VERSION 5.7 ;

BUSBITCHARS "[]" ;
DIVIDERCHAR "/" ;

UNITS
  TIME NANOSECONDS 1 ;
  CAPACITANCE PICOFARADS 1 ;
  RESISTANCE OHMS 1 ;
  DATABASE MICRONS 1000 ;
END UNITS

MANUFACTURINGGRID 0.005 ;

PROPERTYDEFINITIONS
  LAYER LEF58_TYPE STRING ;
END PROPERTYDEFINITIONS

SITE unithd
  SYMMETRY Y ;
  CLASS CORE ;
  SIZE 0.46 BY 2.72 ;
END unithd

SITE unithddbl
  SYMMETRY Y ;
  CLASS CORE ;
  SIZE 0.46 BY 5.44 ;
END unithddbl

LAYER nwell
  TYPE MASTERSLICE ;
 PROPERTY LEF58_TYPE "TYPE NWELL ;" ;
END nwell

LAYER pwell
  TYPE MASTERSLICE ;
 PROPERTY LEF58_TYPE "TYPE PWELL ;" ;
END pwell

LAYER Gate
  TYPE MASTERSLICE ;
END Gate

LAYER Active
  TYPE MASTERSLICE ;
END Active

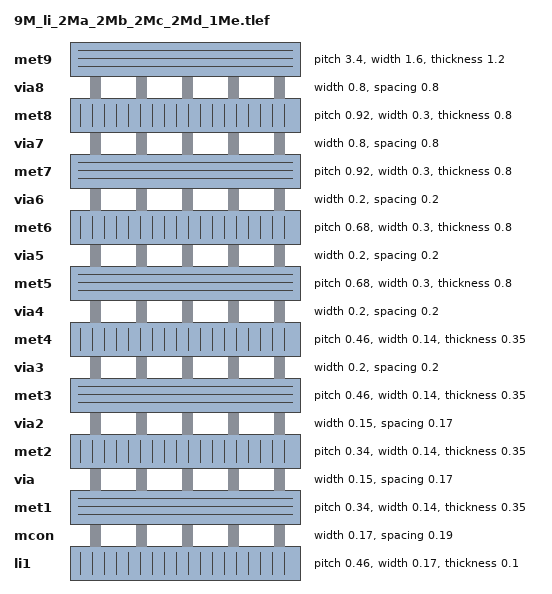
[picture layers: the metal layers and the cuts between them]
LAYER li1
  TYPE ROUTING ;
  DIRECTION VERTICAL ;

  PITCH 0.46 0.34 ;
  OFFSET 0.23 0.17 ;

  WIDTH 0.17 ;
  SPACINGTABLE
     PARALLELRUNLENGTH 0
     WIDTH 0 0.17 ;
  AREA 0.0561 ;
  THICKNESS 0.1 ;
  EDGECAPACITANCE 40.697E-6 ;
  CAPACITANCE CPERSQDIST 36.9866E-6 ;
  RESISTANCE RPERSQ 12.2 ;

  ANTENNAMODEL OXIDE1 ;
  ANTENNADIFFSIDEAREARATIO PWL ( ( 0 75 ) ( 0.0125 75 ) ( 0.0225 85.125 ) ( 22.5 10200 ) ) ;
END li1

LAYER mcon
  TYPE CUT ;

  WIDTH 0.17 ;
  SPACING 0.19 ;
  ENCLOSURE BELOW 0 0 ;
  ENCLOSURE ABOVE 0.03 0.06 ;

  ANTENNADIFFAREARATIO PWL ( ( 0 3 ) ( 0.0125 3 ) ( 0.0225 3.405 ) ( 22.5 408 ) ) ;
  DCCURRENTDENSITY AVERAGE 0.36 ;

END mcon
LAYER met1
  TYPE ROUTING ;
  DIRECTION HORIZONTAL ;

  PITCH 0.34 ;
  OFFSET 0.17 ;

  WIDTH 0.14 ;
  SPACINGTABLE
     PARALLELRUNLENGTH 0
     WIDTH 0 0.14
     WIDTH 3 0.28 ;
  AREA 0.083 ;
  THICKNESS 0.35 ;
  MINENCLOSEDAREA 0.14 ;

  ANTENNAMODEL OXIDE1 ;
  ANTENNADIFFSIDEAREARATIO PWL ( ( 0 400 ) ( 0.0125 400 ) ( 0.0225 2609 ) ( 22.5 11600 ) ) ;

  EDGECAPACITANCE 40.567E-6 ;
  CAPACITANCE CPERSQDIST 25.7784E-6 ;
  DCCURRENTDENSITY AVERAGE 2.8 ;
  ACCURRENTDENSITY RMS 6.1 ;
  MAXIMUMDENSITY 70 ;
  DENSITYCHECKWINDOW 700 700 ;
  DENSITYCHECKSTEP 70 ;

  RESISTANCE RPERSQ 0.125 ;
END met1
LAYER via
  TYPE CUT ;
  WIDTH 0.15 ; 
  SPACING 0.17 ;
  ENCLOSURE BELOW 0.055 0.085 ;
  ENCLOSURE ABOVE 0.055 0.085 ;
  ANTENNADIFFAREARATIO PWL ( ( 0 6 ) ( 0.0125 6 ) ( 0.0225 6.81 ) ( 22.5 816 ) ) ;
  DCCURRENTDENSITY AVERAGE 0.29 ;
END via
LAYER met2
  TYPE ROUTING ;
  DIRECTION VERTICAL ;

  PITCH 0.34 ;
  OFFSET 0.17 ;

  WIDTH 0.14 ;
  SPACINGTABLE
     PARALLELRUNLENGTH 0
     WIDTH 0 0.14
     WIDTH 3 0.28 ;
  AREA 0.083 ;
  THICKNESS 0.35 ;
  MINENCLOSEDAREA 0.14 ;

  ANTENNAMODEL OXIDE1 ;
  ANTENNADIFFSIDEAREARATIO PWL ( ( 0 400 ) ( 0.0125 400 ) ( 0.0225 2609 ) ( 22.5 11600 ) ) ;

  EDGECAPACITANCE 40.567E-6 ;
  CAPACITANCE CPERSQDIST 25.7784E-6 ;
  DCCURRENTDENSITY AVERAGE 2.8 ;
  ACCURRENTDENSITY RMS 6.1 ;
  MAXIMUMDENSITY 70 ;
  DENSITYCHECKWINDOW 700 700 ;
  DENSITYCHECKSTEP 70 ;

  RESISTANCE RPERSQ 0.125 ;
END met2
LAYER via2
  TYPE CUT ;
  WIDTH 0.15 ; 
  SPACING 0.17 ;
  ENCLOSURE BELOW 0.055 0.085 ;
  ENCLOSURE ABOVE 0.055 0.085 ;
  ANTENNADIFFAREARATIO PWL ( ( 0 6 ) ( 0.0125 6 ) ( 0.0225 6.81 ) ( 22.5 816 ) ) ;
  DCCURRENTDENSITY AVERAGE 0.29 ;
END via2
LAYER met3
  TYPE ROUTING ;
  DIRECTION HORIZONTAL ;

  PITCH 0.46 ;
  OFFSET 0.23 ;

  WIDTH 0.14 ; 
  SPACINGTABLE
     PARALLELRUNLENGTH 0
     WIDTH 0 0.14
     WIDTH 3 0.28 ;
  AREA 0.0676 ;
  THICKNESS 0.35 ;
  MINENCLOSEDAREA 0.14 ;

  EDGECAPACITANCE 37.759E-6 ;
  CAPACITANCE CPERSQDIST 16.9423E-6 ;
  RESISTANCE RPERSQ 0.125 ;
  DCCURRENTDENSITY AVERAGE 2.8 ;
  ACCURRENTDENSITY RMS 6.1 ;

  ANTENNAMODEL OXIDE1 ;
  ANTENNADIFFSIDEAREARATIO PWL ( ( 0 400 ) ( 0.0125 400 ) ( 0.0225 2609 ) ( 22.5 11600 ) ) ;

  MAXIMUMDENSITY 70 ;
  DENSITYCHECKWINDOW 700 700 ;
  DENSITYCHECKSTEP 70 ;
END met3
LAYER via3
  TYPE CUT ;
  WIDTH 0.2 ;
  SPACING 0.2 ;
  ENCLOSURE BELOW 0.04 0.085 ;
  ENCLOSURE ABOVE 0.065 0.065 ;
  ANTENNADIFFAREARATIO PWL ( ( 0 6 ) ( 0.0125 6 ) ( 0.0225 6.81 ) ( 22.5 816 ) ) ;
  DCCURRENTDENSITY AVERAGE 0.48 ;
END via3
LAYER met4
  TYPE ROUTING ;
  DIRECTION VERTICAL ;

  PITCH 0.46 ;
  OFFSET 0.23 ;

  WIDTH 0.14 ; 
  SPACINGTABLE
     PARALLELRUNLENGTH 0
     WIDTH 0 0.14
     WIDTH 3 0.28 ;
  AREA 0.0676 ;
  THICKNESS 0.35 ;
  MINENCLOSEDAREA 0.14 ;

  EDGECAPACITANCE 37.759E-6 ;
  CAPACITANCE CPERSQDIST 16.9423E-6 ;
  RESISTANCE RPERSQ 0.125 ;
  DCCURRENTDENSITY AVERAGE 2.8 ;
  ACCURRENTDENSITY RMS 6.1 ;

  ANTENNAMODEL OXIDE1 ;
  ANTENNADIFFSIDEAREARATIO PWL ( ( 0 400 ) ( 0.0125 400 ) ( 0.0225 2609 ) ( 22.5 11600 ) ) ;

  MAXIMUMDENSITY 70 ;
  DENSITYCHECKWINDOW 700 700 ;
  DENSITYCHECKSTEP 70 ;
END met4
LAYER via4
  TYPE CUT ;
  WIDTH 0.2 ;
  SPACING 0.2 ;
  ENCLOSURE BELOW 0.04 0.085 ;
  ENCLOSURE ABOVE 0.065 0.065 ;
  ANTENNADIFFAREARATIO PWL ( ( 0 6 ) ( 0.0125 6 ) ( 0.0225 6.81 ) ( 22.5 816 ) ) ;
  DCCURRENTDENSITY AVERAGE 0.48 ;
END via4
LAYER met5
  TYPE ROUTING ;
  DIRECTION HORIZONTAL ;

  PITCH 0.68 ;
  OFFSET 0.34 ;

  WIDTH 0.3 ;
  SPACINGTABLE
     PARALLELRUNLENGTH 0
     WIDTH 0 0.3
     WIDTH 3 0.4 ;
  AREA 0.24 ;              # Met3 6
  THICKNESS 0.8 ;

  EDGECAPACITANCE 40.989E-6 ;
  CAPACITANCE CPERSQDIST 12.3729E-6 ;
  RESISTANCE RPERSQ 0.047 ;
  DCCURRENTDENSITY AVERAGE 6.8 ;
  ACCURRENTDENSITY RMS 14.9 ;

  ANTENNAMODEL OXIDE1 ;
  ANTENNADIFFSIDEAREARATIO PWL ( ( 0 400 ) ( 0.0125 400 ) ( 0.0225 2609 ) ( 22.5 11600 ) ) ;

  MAXIMUMDENSITY 70 ;
  DENSITYCHECKWINDOW 700 700 ;
  DENSITYCHECKSTEP 70 ;
END met5
LAYER via5
  TYPE CUT ;
  WIDTH 0.2 ;
  SPACING 0.2 ;
  ENCLOSURE BELOW 0.06 0.09 ;
  ENCLOSURE ABOVE 0.065 0.065 ;
  ANTENNADIFFAREARATIO PWL ( ( 0 6 ) ( 0.0125 6 ) ( 0.0225 6.81 ) ( 22.5 816 ) ) ;
  DCCURRENTDENSITY AVERAGE 0.48 ;
END via5
LAYER met6
  TYPE ROUTING ;
  DIRECTION VERTICAL ;

  PITCH 0.68 ;
  OFFSET 0.34 ;

  WIDTH 0.3 ;
  SPACINGTABLE
     PARALLELRUNLENGTH 0
     WIDTH 0 0.3
     WIDTH 3 0.4 ;
  AREA 0.24 ;              # Met3 6
  THICKNESS 0.8 ;

  EDGECAPACITANCE 40.989E-6 ;
  CAPACITANCE CPERSQDIST 12.3729E-6 ;
  RESISTANCE RPERSQ 0.047 ;
  DCCURRENTDENSITY AVERAGE 6.8 ;
  ACCURRENTDENSITY RMS 14.9 ;

  ANTENNAMODEL OXIDE1 ;
  ANTENNADIFFSIDEAREARATIO PWL ( ( 0 400 ) ( 0.0125 400 ) ( 0.0225 2609 ) ( 22.5 11600 ) ) ;

  MAXIMUMDENSITY 70 ;
  DENSITYCHECKWINDOW 700 700 ;
  DENSITYCHECKSTEP 70 ;
END met6
LAYER via6
  TYPE CUT ;
  WIDTH 0.2 ;
  SPACING 0.2 ;
  ENCLOSURE BELOW 0.06 0.09 ;
  ENCLOSURE ABOVE 0.065 0.065 ;
  ANTENNADIFFAREARATIO PWL ( ( 0 6 ) ( 0.0125 6 ) ( 0.0225 6.81 ) ( 22.5 816 ) ) ;
  DCCURRENTDENSITY AVERAGE 0.48 ;
END via6
LAYER met7
  TYPE ROUTING ;
  DIRECTION HORIZONTAL ;


  PITCH 0.92 ;
  OFFSET 0.46 ;

  WIDTH 0.3 ;
  SPACINGTABLE
     PARALLELRUNLENGTH 0
     WIDTH 0 0.3
     WIDTH 3 0.4 ;
  AREA 0.24 ;

  THICKNESS 0.8 ;

  EDGECAPACITANCE 36.676E-6 ;
  CAPACITANCE CPERSQDIST 8.41537E-6 ;
  RESISTANCE RPERSQ 0.047 ;
  DCCURRENTDENSITY AVERAGE 6.8 ;
  ACCURRENTDENSITY RMS 14.9 ;

  ANTENNAMODEL OXIDE1 ;
  ANTENNADIFFSIDEAREARATIO PWL ( ( 0 400 ) ( 0.0125 400 ) ( 0.0225 2609 ) ( 22.5 11600 ) ) ;

  MAXIMUMDENSITY 70 ;
  DENSITYCHECKWINDOW 700 700 ;
  DENSITYCHECKSTEP 70 ;
END met7
LAYER via7
  TYPE CUT ;
  WIDTH 0.8 ;
  SPACING 0.8 ;
  ENCLOSURE BELOW 0.19 0.19 ;
  ENCLOSURE ABOVE 0.31 0.31 ;
  ANTENNADIFFAREARATIO PWL ( ( 0 6 ) ( 0.0125 6 ) ( 0.0225 6.81 ) ( 22.5 816 ) ) ;
  DCCURRENTDENSITY AVERAGE 2.49 ;
END via7
LAYER met8
  TYPE ROUTING ;
  DIRECTION VERTICAL ;


  PITCH 0.92 ;
  OFFSET 0.46 ;

  WIDTH 0.3 ;
  SPACINGTABLE
     PARALLELRUNLENGTH 0
     WIDTH 0 0.3
     WIDTH 3 0.4 ;
  AREA 0.24 ;

  THICKNESS 0.8 ;

  EDGECAPACITANCE 36.676E-6 ;
  CAPACITANCE CPERSQDIST 8.41537E-6 ;
  RESISTANCE RPERSQ 0.047 ;
  DCCURRENTDENSITY AVERAGE 6.8 ;
  ACCURRENTDENSITY RMS 14.9 ;

  ANTENNAMODEL OXIDE1 ;
  ANTENNADIFFSIDEAREARATIO PWL ( ( 0 400 ) ( 0.0125 400 ) ( 0.0225 2609 ) ( 22.5 11600 ) ) ;

  MAXIMUMDENSITY 70 ;
  DENSITYCHECKWINDOW 700 700 ;
  DENSITYCHECKSTEP 70 ;
END met8
LAYER via8
  TYPE CUT ;
  WIDTH 0.8 ;
  SPACING 0.8 ;
  ENCLOSURE BELOW 0.19 0.19 ;
  ENCLOSURE ABOVE 0.31 0.31 ;
  ANTENNADIFFAREARATIO PWL ( ( 0 6 ) ( 0.0125 6 ) ( 0.0225 6.81 ) ( 22.5 816 ) ) ;
  DCCURRENTDENSITY AVERAGE 2.49 ;
END via8
LAYER met9
  TYPE ROUTING ;
  DIRECTION HORIZONTAL ;


  PITCH 3.4 ;
  OFFSET 1.7 ;

  WIDTH 1.6 ;
  SPACINGTABLE
     PARALLELRUNLENGTH 0
     WIDTH 0 1.6 ;
  AREA 4 ;

  THICKNESS 1.2 ;

  EDGECAPACITANCE 38.851E-6 ;
  CAPACITANCE CPERSQDIST 6.32063E-6 ;
  RESISTANCE RPERSQ 0.0285 ;
  DCCURRENTDENSITY AVERAGE 10.17 ;
  ACCURRENTDENSITY RMS 22.34 ;

  ANTENNAMODEL OXIDE1 ;
  ANTENNADIFFSIDEAREARATIO PWL ( ( 0 400 ) ( 0.0125 400 ) ( 0.0225 2609 ) ( 22.5 11600 ) ) ;
END met9
### Routing via cells section   ###
# Plus via rule, metals are along the prefered direction
VIA L1M1_PR DEFAULT
  LAYER mcon ;
  RECT -0.085 -0.085 0.085 0.085 ;
  LAYER li1 ;
  RECT -0.085 -0.085 0.085 0.085 ;
  LAYER met1 ;
  RECT -0.145 -0.115 0.145 0.115 ;
END L1M1_PR

VIARULE L1M1_PR GENERATE
  LAYER li1 ;
  ENCLOSURE 0 0 ;
  LAYER met1 ;
  ENCLOSURE 0.06 0.03 ;
  LAYER mcon ;
  RECT -0.085 -0.085 0.085 0.085 ;
  SPACING 0.36 BY 0.36 ;
END L1M1_PR

# Plus via rule, metals are along the non prefered direction
VIA L1M1_PR_R DEFAULT
  LAYER mcon ;
  RECT -0.085 -0.085 0.085 0.085 ;
  LAYER li1 ;
  RECT -0.085 -0.085 0.085 0.085 ;
  LAYER met1 ;
  RECT -0.115 -0.145 0.115 0.145 ;
END L1M1_PR_R

VIARULE L1M1_PR_R GENERATE
  LAYER li1 ;
  ENCLOSURE 0 0 ;
  LAYER met1 ;
  ENCLOSURE 0.03 0.06 ;
  LAYER mcon ;
  RECT -0.085 -0.085 0.085 0.085 ;
  SPACING 0.36 BY 0.36 ;
END L1M1_PR_R

# Minus via rule, lower layer metal is along prefered direction
VIA L1M1_PR_M DEFAULT
  LAYER mcon ;
  RECT -0.085 -0.085 0.085 0.085 ;
  LAYER li1 ;
  RECT -0.085 -0.085 0.085 0.085 ;
  LAYER met1 ;
  RECT -0.115 -0.145 0.115 0.145 ;
END L1M1_PR_M

VIARULE L1M1_PR_M GENERATE
  LAYER li1 ;
  ENCLOSURE 0 0 ;
  LAYER met1 ;
  ENCLOSURE 0.03 0.06 ;
  LAYER mcon ;
  RECT -0.085 -0.085 0.085 0.085 ;
  SPACING 0.36 BY 0.36 ;
END L1M1_PR_M

# Minus via rule, upper layer metal is along prefered direction
VIA L1M1_PR_MR DEFAULT
  LAYER mcon ;
  RECT -0.085 -0.085 0.085 0.085 ;
  LAYER li1 ;
  RECT -0.085 -0.085 0.085 0.085 ;
  LAYER met1 ;
  RECT -0.145 -0.115 0.145 0.115 ;
END L1M1_PR_MR

VIARULE L1M1_PR_MR GENERATE
  LAYER li1 ;
  ENCLOSURE 0 0 ;
  LAYER met1 ;
  ENCLOSURE 0.06 0.03 ;
  LAYER mcon ;
  RECT -0.085 -0.085 0.085 0.085 ;
  SPACING 0.36 BY 0.36 ;
END L1M1_PR_MR

# Centered via rule, we really do not want to use it
VIA L1M1_PR_C DEFAULT
  LAYER mcon ;
  RECT -0.085 -0.085 0.085 0.085 ;
  LAYER li1 ;
  RECT -0.085 -0.085 0.085 0.085 ;
  LAYER met1 ;
  RECT -0.145 -0.145 0.145 0.145 ;
END L1M1_PR_C

VIARULE L1M1_PR_C GENERATE
  LAYER li1 ;
  ENCLOSURE 0 0 ;
  LAYER met1 ;
  ENCLOSURE 0.06 0.06 ;
  LAYER mcon ;
  RECT -0.085 -0.085 0.085 0.085 ;
  SPACING 0.36 BY 0.36 ;
END L1M1_PR_C
# Plus via rule, metals are along the prefered direction
VIA M1M2_PR DEFAULT
  LAYER via ;
  RECT -0.075 -0.075 0.075 0.075 ;
  LAYER met1 ;
  RECT -0.160 -0.130 0.160 0.130 ;
  LAYER met2 ;
  RECT -0.130 -0.160 0.130 0.160 ;
END M1M2_PR

VIARULE M1M2_PR GENERATE
  LAYER met1 ;
  ENCLOSURE 0.085 0.055 ;
  LAYER met2 ;
  ENCLOSURE 0.055 0.085 ;
  LAYER via ;
  RECT -0.075 -0.075 0.075 0.075 ;
  SPACING 0.32 BY 0.32 ;
END M1M2_PR

# Plus via rule, metals are along the non prefered direction
VIA M1M2_PR_R DEFAULT
  LAYER via ;
  RECT -0.075 -0.075 0.075 0.075 ;
  LAYER met1 ;
  RECT -0.130 -0.160 0.130 0.160 ;
  LAYER met2 ;
  RECT -0.160 -0.130 0.160 0.130 ;
END M1M2_PR_R

VIARULE M1M2_PR_R GENERATE
  LAYER met1 ;
  ENCLOSURE 0.055 0.085 ;
  LAYER met2 ;
  ENCLOSURE 0.085 0.055 ;
  LAYER via ;
  RECT -0.075 -0.075 0.075 0.075 ;
  SPACING 0.32 BY 0.32 ;
END M1M2_PR_R

# Minus via rule, lower layer metal is along prefered direction
VIA M1M2_PR_M DEFAULT
  LAYER via ;
  RECT -0.075 -0.075 0.075 0.075 ;
  LAYER met1 ;
  RECT -0.160 -0.130 0.160 0.130 ;
  LAYER met2 ;
  RECT -0.160 -0.130 0.160 0.130 ;
END M1M2_PR_M

VIARULE M1M2_PR_M GENERATE
  LAYER met1 ;
  ENCLOSURE 0.085 0.055 ;
  LAYER met2 ;
  ENCLOSURE 0.085 0.055 ;
  LAYER via ;
  RECT -0.075 -0.075 0.075 0.075 ;
  SPACING 0.32 BY 0.32 ;
END M1M2_PR_M

# Minus via rule, upper layer metal is along prefered direction
VIA M1M2_PR_MR DEFAULT
  LAYER via ;
  RECT -0.075 -0.075 0.075 0.075 ;
  LAYER met1 ;
  RECT -0.130 -0.160 0.130 0.160 ;
  LAYER met2 ;
  RECT -0.130 -0.160 0.130 0.160 ;
END M1M2_PR_MR

VIARULE M1M2_PR_MR GENERATE
  LAYER met1 ;
  ENCLOSURE 0.055 0.085 ;
  LAYER met2 ;
  ENCLOSURE 0.055 0.085 ;
  LAYER via ;
  RECT -0.075 -0.075 0.075 0.075 ;
  SPACING 0.32 BY 0.32 ;
END M1M2_PR_MR

# Centered via rule, we really do not want to use it
VIA M1M2_PR_C DEFAULT
  LAYER via ;
  RECT -0.075 -0.075 0.075 0.075 ;
  LAYER met1 ;
  RECT -0.160 -0.160 0.160 0.160 ;
  LAYER met2 ;
  RECT -0.160 -0.160 0.160 0.160 ;
END M1M2_PR_C

VIARULE M1M2_PR_C GENERATE
  LAYER met1 ;
  ENCLOSURE 0.085 0.085 ;
  LAYER met2 ;
  ENCLOSURE 0.085 0.085 ;
  LAYER via ;
  RECT -0.075 -0.075 0.075 0.075 ;
  SPACING 0.32 BY 0.32 ;
END M1M2_PR_C
# Plus via rule, metals are along the prefered direction
VIA M2M3_PR DEFAULT
  LAYER via2 ;
  RECT -0.075 -0.075 0.075 0.075 ;
  LAYER met2 ;
  RECT -0.160 -0.130 0.160 0.130 ;
  LAYER met3 ;
  RECT -0.130 -0.160 0.130 0.160 ;
END M2M3_PR

VIARULE M2M3_PR GENERATE
  LAYER met2 ;
  ENCLOSURE 0.085 0.055 ;
  LAYER met3 ;
  ENCLOSURE 0.055 0.085 ;
  LAYER via2 ;
  RECT -0.075 -0.075 0.075 0.075 ;
  SPACING 0.32 BY 0.32 ;
END M2M3_PR

# Plus via rule, metals are along the non prefered direction
VIA M2M3_PR_R DEFAULT
  LAYER via2 ;
  RECT -0.075 -0.075 0.075 0.075 ;
  LAYER met2 ;
  RECT -0.130 -0.160 0.130 0.160 ;
  LAYER met3 ;
  RECT -0.160 -0.130 0.160 0.130 ;
END M2M3_PR_R

VIARULE M2M3_PR_R GENERATE
  LAYER met2 ;
  ENCLOSURE 0.055 0.085 ;
  LAYER met3 ;
  ENCLOSURE 0.085 0.055 ;
  LAYER via2 ;
  RECT -0.075 -0.075 0.075 0.075 ;
  SPACING 0.32 BY 0.32 ;
END M2M3_PR_R

# Minus via rule, lower layer metal is along prefered direction
VIA M2M3_PR_M DEFAULT
  LAYER via2 ;
  RECT -0.075 -0.075 0.075 0.075 ;
  LAYER met2 ;
  RECT -0.160 -0.130 0.160 0.130 ;
  LAYER met3 ;
  RECT -0.160 -0.130 0.160 0.130 ;
END M2M3_PR_M

VIARULE M2M3_PR_M GENERATE
  LAYER met2 ;
  ENCLOSURE 0.085 0.055 ;
  LAYER met3 ;
  ENCLOSURE 0.085 0.055 ;
  LAYER via2 ;
  RECT -0.075 -0.075 0.075 0.075 ;
  SPACING 0.32 BY 0.32 ;
END M2M3_PR_M

# Minus via rule, upper layer metal is along prefered direction
VIA M2M3_PR_MR DEFAULT
  LAYER via2 ;
  RECT -0.075 -0.075 0.075 0.075 ;
  LAYER met2 ;
  RECT -0.130 -0.160 0.130 0.160 ;
  LAYER met3 ;
  RECT -0.130 -0.160 0.130 0.160 ;
END M2M3_PR_MR

VIARULE M2M3_PR_MR GENERATE
  LAYER met2 ;
  ENCLOSURE 0.055 0.085 ;
  LAYER met3 ;
  ENCLOSURE 0.055 0.085 ;
  LAYER via2 ;
  RECT -0.075 -0.075 0.075 0.075 ;
  SPACING 0.32 BY 0.32 ;
END M2M3_PR_MR

# Centered via rule, we really do not want to use it
VIA M2M3_PR_C DEFAULT
  LAYER via2 ;
  RECT -0.075 -0.075 0.075 0.075 ;
  LAYER met2 ;
  RECT -0.160 -0.160 0.160 0.160 ;
  LAYER met3 ;
  RECT -0.160 -0.160 0.160 0.160 ;
END M2M3_PR_C

VIARULE M2M3_PR_C GENERATE
  LAYER met2 ;
  ENCLOSURE 0.085 0.085 ;
  LAYER met3 ;
  ENCLOSURE 0.085 0.085 ;
  LAYER via2 ;
  RECT -0.075 -0.075 0.075 0.075 ;
  SPACING 0.32 BY 0.32 ;
END M2M3_PR_C
# Plus via rule, metals are along the prefered direction
VIA M3M4_PR DEFAULT
  LAYER via3 ;
  RECT -0.100 -0.100 0.100 0.100 ;
  LAYER met3 ;
  RECT -0.185 -0.140 0.185 0.140 ;
  LAYER met4 ;
  RECT -0.165 -0.165 0.165 0.165 ;
END M3M4_PR

VIARULE M3M4_PR GENERATE
  LAYER met3 ;
  ENCLOSURE 0.085 0.04 ;
  LAYER met4 ;
  ENCLOSURE 0.065 0.065 ;
  LAYER via3 ;
  RECT -0.100 -0.100 0.100 0.100 ;
  SPACING 0.4 BY 0.4 ;
END M3M4_PR

# Plus via rule, metals are along the non prefered direction
VIA M3M4_PR_R DEFAULT
  LAYER via3 ;
  RECT -0.100 -0.100 0.100 0.100 ;
  LAYER met3 ;
  RECT -0.140 -0.185 0.140 0.185 ;
  LAYER met4 ;
  RECT -0.165 -0.165 0.165 0.165 ;
END M3M4_PR_R

VIARULE M3M4_PR_R GENERATE
  LAYER met3 ;
  ENCLOSURE 0.04 0.085 ;
  LAYER met4 ;
  ENCLOSURE 0.065 0.065 ;
  LAYER via3 ;
  RECT -0.100 -0.100 0.100 0.100 ;
  SPACING 0.4 BY 0.4 ;
END M3M4_PR_R

# Minus via rule, lower layer metal is along prefered direction
VIA M3M4_PR_M DEFAULT
  LAYER via3 ;
  RECT -0.100 -0.100 0.100 0.100 ;
  LAYER met3 ;
  RECT -0.185 -0.140 0.185 0.140 ;
  LAYER met4 ;
  RECT -0.165 -0.165 0.165 0.165 ;
END M3M4_PR_M

VIARULE M3M4_PR_M GENERATE
  LAYER met3 ;
  ENCLOSURE 0.085 0.04 ;
  LAYER met4 ;
  ENCLOSURE 0.065 0.065 ;
  LAYER via3 ;
  RECT -0.100 -0.100 0.100 0.100 ;
  SPACING 0.4 BY 0.4 ;
END M3M4_PR_M

# Minus via rule, upper layer metal is along prefered direction
VIA M3M4_PR_MR DEFAULT
  LAYER via3 ;
  RECT -0.100 -0.100 0.100 0.100 ;
  LAYER met3 ;
  RECT -0.140 -0.185 0.140 0.185 ;
  LAYER met4 ;
  RECT -0.165 -0.165 0.165 0.165 ;
END M3M4_PR_MR

VIARULE M3M4_PR_MR GENERATE
  LAYER met3 ;
  ENCLOSURE 0.04 0.085 ;
  LAYER met4 ;
  ENCLOSURE 0.065 0.065 ;
  LAYER via3 ;
  RECT -0.100 -0.100 0.100 0.100 ;
  SPACING 0.4 BY 0.4 ;
END M3M4_PR_MR

# Centered via rule, we really do not want to use it
VIA M3M4_PR_C DEFAULT
  LAYER via3 ;
  RECT -0.100 -0.100 0.100 0.100 ;
  LAYER met3 ;
  RECT -0.185 -0.185 0.185 0.185 ;
  LAYER met4 ;
  RECT -0.165 -0.165 0.165 0.165 ;
END M3M4_PR_C

VIARULE M3M4_PR_C GENERATE
  LAYER met3 ;
  ENCLOSURE 0.085 0.085 ;
  LAYER met4 ;
  ENCLOSURE 0.065 0.065 ;
  LAYER via3 ;
  RECT -0.100 -0.100 0.100 0.100 ;
  SPACING 0.4 BY 0.4 ;
END M3M4_PR_C
# Plus via rule, metals are along the prefered direction
VIA M4M5_PR DEFAULT
  LAYER via4 ;
  RECT -0.100 -0.100 0.100 0.100 ;
  LAYER met4 ;
  RECT -0.185 -0.140 0.185 0.140 ;
  LAYER met5 ;
  RECT -0.165 -0.165 0.165 0.165 ;
END M4M5_PR

VIARULE M4M5_PR GENERATE
  LAYER met4 ;
  ENCLOSURE 0.085 0.04 ;
  LAYER met5 ;
  ENCLOSURE 0.065 0.065 ;
  LAYER via4 ;
  RECT -0.100 -0.100 0.100 0.100 ;
  SPACING 0.4 BY 0.4 ;
END M4M5_PR

# Plus via rule, metals are along the non prefered direction
VIA M4M5_PR_R DEFAULT
  LAYER via4 ;
  RECT -0.100 -0.100 0.100 0.100 ;
  LAYER met4 ;
  RECT -0.140 -0.185 0.140 0.185 ;
  LAYER met5 ;
  RECT -0.165 -0.165 0.165 0.165 ;
END M4M5_PR_R

VIARULE M4M5_PR_R GENERATE
  LAYER met4 ;
  ENCLOSURE 0.04 0.085 ;
  LAYER met5 ;
  ENCLOSURE 0.065 0.065 ;
  LAYER via4 ;
  RECT -0.100 -0.100 0.100 0.100 ;
  SPACING 0.4 BY 0.4 ;
END M4M5_PR_R

# Minus via rule, lower layer metal is along prefered direction
VIA M4M5_PR_M DEFAULT
  LAYER via4 ;
  RECT -0.100 -0.100 0.100 0.100 ;
  LAYER met4 ;
  RECT -0.185 -0.140 0.185 0.140 ;
  LAYER met5 ;
  RECT -0.165 -0.165 0.165 0.165 ;
END M4M5_PR_M

VIARULE M4M5_PR_M GENERATE
  LAYER met4 ;
  ENCLOSURE 0.085 0.04 ;
  LAYER met5 ;
  ENCLOSURE 0.065 0.065 ;
  LAYER via4 ;
  RECT -0.100 -0.100 0.100 0.100 ;
  SPACING 0.4 BY 0.4 ;
END M4M5_PR_M

# Minus via rule, upper layer metal is along prefered direction
VIA M4M5_PR_MR DEFAULT
  LAYER via4 ;
  RECT -0.100 -0.100 0.100 0.100 ;
  LAYER met4 ;
  RECT -0.140 -0.185 0.140 0.185 ;
  LAYER met5 ;
  RECT -0.165 -0.165 0.165 0.165 ;
END M4M5_PR_MR

VIARULE M4M5_PR_MR GENERATE
  LAYER met4 ;
  ENCLOSURE 0.04 0.085 ;
  LAYER met5 ;
  ENCLOSURE 0.065 0.065 ;
  LAYER via4 ;
  RECT -0.100 -0.100 0.100 0.100 ;
  SPACING 0.4 BY 0.4 ;
END M4M5_PR_MR

# Centered via rule, we really do not want to use it
VIA M4M5_PR_C DEFAULT
  LAYER via4 ;
  RECT -0.100 -0.100 0.100 0.100 ;
  LAYER met4 ;
  RECT -0.185 -0.185 0.185 0.185 ;
  LAYER met5 ;
  RECT -0.165 -0.165 0.165 0.165 ;
END M4M5_PR_C

VIARULE M4M5_PR_C GENERATE
  LAYER met4 ;
  ENCLOSURE 0.085 0.085 ;
  LAYER met5 ;
  ENCLOSURE 0.065 0.065 ;
  LAYER via4 ;
  RECT -0.100 -0.100 0.100 0.100 ;
  SPACING 0.4 BY 0.4 ;
END M4M5_PR_C
# Plus via rule, metals are along the prefered direction
VIA M5M6_PR DEFAULT
  LAYER via5 ;
  RECT -0.100 -0.100 0.100 0.100 ;
  LAYER met5 ;
  RECT -0.190 -0.160 0.190 0.160 ;
  LAYER met6 ;
  RECT -0.165 -0.165 0.165 0.165 ;
END M5M6_PR

VIARULE M5M6_PR GENERATE
  LAYER met5 ;
  ENCLOSURE 0.09 0.06 ;
  LAYER met6 ;
  ENCLOSURE 0.065 0.065 ;
  LAYER via5 ;
  RECT -0.100 -0.100 0.100 0.100 ;
  SPACING 0.4 BY 0.4 ;
END M5M6_PR

# Plus via rule, metals are along the non prefered direction
VIA M5M6_PR_R DEFAULT
  LAYER via5 ;
  RECT -0.100 -0.100 0.100 0.100 ;
  LAYER met5 ;
  RECT -0.160 -0.190 0.160 0.190 ;
  LAYER met6 ;
  RECT -0.165 -0.165 0.165 0.165 ;
END M5M6_PR_R

VIARULE M5M6_PR_R GENERATE
  LAYER met5 ;
  ENCLOSURE 0.06 0.09 ;
  LAYER met6 ;
  ENCLOSURE 0.065 0.065 ;
  LAYER via5 ;
  RECT -0.100 -0.100 0.100 0.100 ;
  SPACING 0.4 BY 0.4 ;
END M5M6_PR_R

# Minus via rule, lower layer metal is along prefered direction
VIA M5M6_PR_M DEFAULT
  LAYER via5 ;
  RECT -0.100 -0.100 0.100 0.100 ;
  LAYER met5 ;
  RECT -0.190 -0.160 0.190 0.160 ;
  LAYER met6 ;
  RECT -0.165 -0.165 0.165 0.165 ;
END M5M6_PR_M

VIARULE M5M6_PR_M GENERATE
  LAYER met5 ;
  ENCLOSURE 0.09 0.06 ;
  LAYER met6 ;
  ENCLOSURE 0.065 0.065 ;
  LAYER via5 ;
  RECT -0.100 -0.100 0.100 0.100 ;
  SPACING 0.4 BY 0.4 ;
END M5M6_PR_M

# Minus via rule, upper layer metal is along prefered direction
VIA M5M6_PR_MR DEFAULT
  LAYER via5 ;
  RECT -0.100 -0.100 0.100 0.100 ;
  LAYER met5 ;
  RECT -0.160 -0.190 0.160 0.190 ;
  LAYER met6 ;
  RECT -0.165 -0.165 0.165 0.165 ;
END M5M6_PR_MR

VIARULE M5M6_PR_MR GENERATE
  LAYER met5 ;
  ENCLOSURE 0.06 0.09 ;
  LAYER met6 ;
  ENCLOSURE 0.065 0.065 ;
  LAYER via5 ;
  RECT -0.100 -0.100 0.100 0.100 ;
  SPACING 0.4 BY 0.4 ;
END M5M6_PR_MR

# Centered via rule, we really do not want to use it
VIA M5M6_PR_C DEFAULT
  LAYER via5 ;
  RECT -0.100 -0.100 0.100 0.100 ;
  LAYER met5 ;
  RECT -0.190 -0.190 0.190 0.190 ;
  LAYER met6 ;
  RECT -0.165 -0.165 0.165 0.165 ;
END M5M6_PR_C

VIARULE M5M6_PR_C GENERATE
  LAYER met5 ;
  ENCLOSURE 0.09 0.09 ;
  LAYER met6 ;
  ENCLOSURE 0.065 0.065 ;
  LAYER via5 ;
  RECT -0.100 -0.100 0.100 0.100 ;
  SPACING 0.4 BY 0.4 ;
END M5M6_PR_C
# Plus via rule, metals are along the prefered direction
VIA M6M7_PR DEFAULT
  LAYER via6 ;
  RECT -0.100 -0.100 0.100 0.100 ;
  LAYER met6 ;
  RECT -0.190 -0.160 0.190 0.160 ;
  LAYER met7 ;
  RECT -0.165 -0.165 0.165 0.165 ;
END M6M7_PR

VIARULE M6M7_PR GENERATE
  LAYER met6 ;
  ENCLOSURE 0.09 0.06 ;
  LAYER met7 ;
  ENCLOSURE 0.065 0.065 ;
  LAYER via6 ;
  RECT -0.100 -0.100 0.100 0.100 ;
  SPACING 0.4 BY 0.4 ;
END M6M7_PR

# Plus via rule, metals are along the non prefered direction
VIA M6M7_PR_R DEFAULT
  LAYER via6 ;
  RECT -0.100 -0.100 0.100 0.100 ;
  LAYER met6 ;
  RECT -0.160 -0.190 0.160 0.190 ;
  LAYER met7 ;
  RECT -0.165 -0.165 0.165 0.165 ;
END M6M7_PR_R

VIARULE M6M7_PR_R GENERATE
  LAYER met6 ;
  ENCLOSURE 0.06 0.09 ;
  LAYER met7 ;
  ENCLOSURE 0.065 0.065 ;
  LAYER via6 ;
  RECT -0.100 -0.100 0.100 0.100 ;
  SPACING 0.4 BY 0.4 ;
END M6M7_PR_R

# Minus via rule, lower layer metal is along prefered direction
VIA M6M7_PR_M DEFAULT
  LAYER via6 ;
  RECT -0.100 -0.100 0.100 0.100 ;
  LAYER met6 ;
  RECT -0.190 -0.160 0.190 0.160 ;
  LAYER met7 ;
  RECT -0.165 -0.165 0.165 0.165 ;
END M6M7_PR_M

VIARULE M6M7_PR_M GENERATE
  LAYER met6 ;
  ENCLOSURE 0.09 0.06 ;
  LAYER met7 ;
  ENCLOSURE 0.065 0.065 ;
  LAYER via6 ;
  RECT -0.100 -0.100 0.100 0.100 ;
  SPACING 0.4 BY 0.4 ;
END M6M7_PR_M

# Minus via rule, upper layer metal is along prefered direction
VIA M6M7_PR_MR DEFAULT
  LAYER via6 ;
  RECT -0.100 -0.100 0.100 0.100 ;
  LAYER met6 ;
  RECT -0.160 -0.190 0.160 0.190 ;
  LAYER met7 ;
  RECT -0.165 -0.165 0.165 0.165 ;
END M6M7_PR_MR

VIARULE M6M7_PR_MR GENERATE
  LAYER met6 ;
  ENCLOSURE 0.06 0.09 ;
  LAYER met7 ;
  ENCLOSURE 0.065 0.065 ;
  LAYER via6 ;
  RECT -0.100 -0.100 0.100 0.100 ;
  SPACING 0.4 BY 0.4 ;
END M6M7_PR_MR

# Centered via rule, we really do not want to use it
VIA M6M7_PR_C DEFAULT
  LAYER via6 ;
  RECT -0.100 -0.100 0.100 0.100 ;
  LAYER met6 ;
  RECT -0.190 -0.190 0.190 0.190 ;
  LAYER met7 ;
  RECT -0.165 -0.165 0.165 0.165 ;
END M6M7_PR_C

VIARULE M6M7_PR_C GENERATE
  LAYER met6 ;
  ENCLOSURE 0.09 0.09 ;
  LAYER met7 ;
  ENCLOSURE 0.065 0.065 ;
  LAYER via6 ;
  RECT -0.100 -0.100 0.100 0.100 ;
  SPACING 0.4 BY 0.4 ;
END M6M7_PR_C
# Plus via rule, metals are along the prefered direction
VIA M7M8_PR DEFAULT
  LAYER via7 ;
  RECT -0.400 -0.400 0.400 0.400 ;
  LAYER met7 ;
  RECT -0.590 -0.590 0.590 0.590 ;
  LAYER met8 ;
  RECT -0.710 -0.710 0.710 0.710 ;
END M7M8_PR

VIARULE M7M8_PR GENERATE
  LAYER met7 ;
  ENCLOSURE 0.19 0.19 ;
  LAYER met8 ;
  ENCLOSURE 0.31 0.31 ;
  LAYER via7 ;
  RECT -0.400 -0.400 0.400 0.400 ;
  SPACING 1.6 BY 1.6 ;
END M7M8_PR

# Plus via rule, metals are along the non prefered direction
VIA M7M8_PR_R DEFAULT
  LAYER via7 ;
  RECT -0.400 -0.400 0.400 0.400 ;
  LAYER met7 ;
  RECT -0.590 -0.590 0.590 0.590 ;
  LAYER met8 ;
  RECT -0.710 -0.710 0.710 0.710 ;
END M7M8_PR_R

VIARULE M7M8_PR_R GENERATE
  LAYER met7 ;
  ENCLOSURE 0.19 0.19 ;
  LAYER met8 ;
  ENCLOSURE 0.31 0.31 ;
  LAYER via7 ;
  RECT -0.400 -0.400 0.400 0.400 ;
  SPACING 1.6 BY 1.6 ;
END M7M8_PR_R

# Minus via rule, lower layer metal is along prefered direction
VIA M7M8_PR_M DEFAULT
  LAYER via7 ;
  RECT -0.400 -0.400 0.400 0.400 ;
  LAYER met7 ;
  RECT -0.590 -0.590 0.590 0.590 ;
  LAYER met8 ;
  RECT -0.710 -0.710 0.710 0.710 ;
END M7M8_PR_M

VIARULE M7M8_PR_M GENERATE
  LAYER met7 ;
  ENCLOSURE 0.19 0.19 ;
  LAYER met8 ;
  ENCLOSURE 0.31 0.31 ;
  LAYER via7 ;
  RECT -0.400 -0.400 0.400 0.400 ;
  SPACING 1.6 BY 1.6 ;
END M7M8_PR_M

# Minus via rule, upper layer metal is along prefered direction
VIA M7M8_PR_MR DEFAULT
  LAYER via7 ;
  RECT -0.400 -0.400 0.400 0.400 ;
  LAYER met7 ;
  RECT -0.590 -0.590 0.590 0.590 ;
  LAYER met8 ;
  RECT -0.710 -0.710 0.710 0.710 ;
END M7M8_PR_MR

VIARULE M7M8_PR_MR GENERATE
  LAYER met7 ;
  ENCLOSURE 0.19 0.19 ;
  LAYER met8 ;
  ENCLOSURE 0.31 0.31 ;
  LAYER via7 ;
  RECT -0.400 -0.400 0.400 0.400 ;
  SPACING 1.6 BY 1.6 ;
END M7M8_PR_MR

# Centered via rule, we really do not want to use it
VIA M7M8_PR_C DEFAULT
  LAYER via7 ;
  RECT -0.400 -0.400 0.400 0.400 ;
  LAYER met7 ;
  RECT -0.590 -0.590 0.590 0.590 ;
  LAYER met8 ;
  RECT -0.710 -0.710 0.710 0.710 ;
END M7M8_PR_C

VIARULE M7M8_PR_C GENERATE
  LAYER met7 ;
  ENCLOSURE 0.19 0.19 ;
  LAYER met8 ;
  ENCLOSURE 0.31 0.31 ;
  LAYER via7 ;
  RECT -0.400 -0.400 0.400 0.400 ;
  SPACING 1.6 BY 1.6 ;
END M7M8_PR_C
# Plus via rule, metals are along the prefered direction
VIA M8M9_PR DEFAULT
  LAYER via8 ;
  RECT -0.400 -0.400 0.400 0.400 ;
  LAYER met8 ;
  RECT -0.590 -0.590 0.590 0.590 ;
  LAYER met9 ;
  RECT -0.710 -0.710 0.710 0.710 ;
END M8M9_PR

VIARULE M8M9_PR GENERATE
  LAYER met8 ;
  ENCLOSURE 0.19 0.19 ;
  LAYER met9 ;
  ENCLOSURE 0.31 0.31 ;
  LAYER via8 ;
  RECT -0.400 -0.400 0.400 0.400 ;
  SPACING 1.6 BY 1.6 ;
END M8M9_PR

# Plus via rule, metals are along the non prefered direction
VIA M8M9_PR_R DEFAULT
  LAYER via8 ;
  RECT -0.400 -0.400 0.400 0.400 ;
  LAYER met8 ;
  RECT -0.590 -0.590 0.590 0.590 ;
  LAYER met9 ;
  RECT -0.710 -0.710 0.710 0.710 ;
END M8M9_PR_R

VIARULE M8M9_PR_R GENERATE
  LAYER met8 ;
  ENCLOSURE 0.19 0.19 ;
  LAYER met9 ;
  ENCLOSURE 0.31 0.31 ;
  LAYER via8 ;
  RECT -0.400 -0.400 0.400 0.400 ;
  SPACING 1.6 BY 1.6 ;
END M8M9_PR_R

# Minus via rule, lower layer metal is along prefered direction
VIA M8M9_PR_M DEFAULT
  LAYER via8 ;
  RECT -0.400 -0.400 0.400 0.400 ;
  LAYER met8 ;
  RECT -0.590 -0.590 0.590 0.590 ;
  LAYER met9 ;
  RECT -0.710 -0.710 0.710 0.710 ;
END M8M9_PR_M

VIARULE M8M9_PR_M GENERATE
  LAYER met8 ;
  ENCLOSURE 0.19 0.19 ;
  LAYER met9 ;
  ENCLOSURE 0.31 0.31 ;
  LAYER via8 ;
  RECT -0.400 -0.400 0.400 0.400 ;
  SPACING 1.6 BY 1.6 ;
END M8M9_PR_M

# Minus via rule, upper layer metal is along prefered direction
VIA M8M9_PR_MR DEFAULT
  LAYER via8 ;
  RECT -0.400 -0.400 0.400 0.400 ;
  LAYER met8 ;
  RECT -0.590 -0.590 0.590 0.590 ;
  LAYER met9 ;
  RECT -0.710 -0.710 0.710 0.710 ;
END M8M9_PR_MR

VIARULE M8M9_PR_MR GENERATE
  LAYER met8 ;
  ENCLOSURE 0.19 0.19 ;
  LAYER met9 ;
  ENCLOSURE 0.31 0.31 ;
  LAYER via8 ;
  RECT -0.400 -0.400 0.400 0.400 ;
  SPACING 1.6 BY 1.6 ;
END M8M9_PR_MR

# Centered via rule, we really do not want to use it
VIA M8M9_PR_C DEFAULT
  LAYER via8 ;
  RECT -0.400 -0.400 0.400 0.400 ;
  LAYER met8 ;
  RECT -0.590 -0.590 0.590 0.590 ;
  LAYER met9 ;
  RECT -0.710 -0.710 0.710 0.710 ;
END M8M9_PR_C

VIARULE M8M9_PR_C GENERATE
  LAYER met8 ;
  ENCLOSURE 0.19 0.19 ;
  LAYER met9 ;
  ENCLOSURE 0.31 0.31 ;
  LAYER via8 ;
  RECT -0.400 -0.400 0.400 0.400 ;
  SPACING 1.6 BY 1.6 ;
END M8M9_PR_C
END LIBRARY
